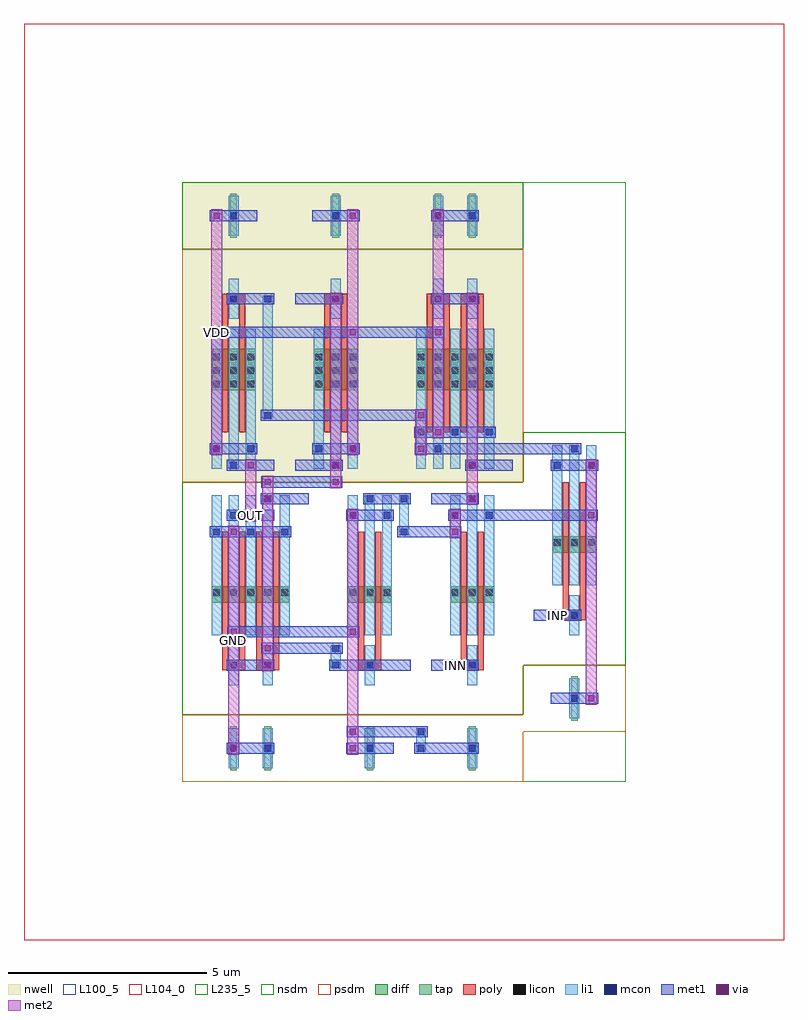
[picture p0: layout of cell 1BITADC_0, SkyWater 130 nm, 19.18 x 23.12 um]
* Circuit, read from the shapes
.subckt 1BITADC_0 GND INN INP OUT VDD
XM1 OUT n1 GND GND sky130_fd_pr__nfet_01v8 w=0.42 l=0.15 m=2
XM2 n1 n1 GND GND sky130_fd_pr__nfet_01v8 w=0.42 l=0.15 m=2
XM3 GND n1 GND GND sky130_fd_pr__nfet_01v8 w=0.42 l=0.15 m=2
XM4 n2 INN GND GND sky130_fd_pr__nfet_01v8 w=0.42 l=0.15 m=2
XM5 n3 INP GND GND sky130_fd_pr__nfet_01v8 w=0.42 l=0.15 m=2
XM6 OUT n3 VDD VDD sky130_fd_pr__pfet_01v8 w=1.05 l=0.15 m=2
XM7 n1 n1 VDD VDD sky130_fd_pr__pfet_01v8 w=1.05 l=0.15 m=2
XM8 n3 n2 VDD VDD sky130_fd_pr__pfet_01v8 w=1.05 l=0.15 m=2
XM9 n2 n2 VDD VDD sky130_fd_pr__pfet_01v8 w=1.05 l=0.15 m=2
.ends

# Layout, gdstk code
from math import pi, radians
import gdstk
lib = gdstk.Library(unit=1e-6, precision=1e-09)
def R(c, l, rs):  # rectangles x0, y0, x1, y1
    for r in rs: c.add(gdstk.rectangle(r[:2], r[2:], *l))
def A(c, l, x, y, w, h, nx, ny, dx, dy):  # array of equal rectangles
    R(c, l, [(x+i*dx, y+j*dy, x+i*dx+w, y+j*dy+h) for i in range(nx) for j in range(ny)])
def P(c, l, *ps):  # polygons
    for p in ps: c.add(gdstk.Polygon(p, *l))
nwell = (64, 20)
diff = (65, 20)
tap = (65, 44)
poly = (66, 20)
licon = (66, 44)
li1 = (67, 20)
mcon = (67, 44)
met1 = (68, 20)
via = (68, 44)
met2 = (69, 20)
nsdm = (93, 44)
psdm = (94, 20)
L100_5 = (100, 5)
L104_0 = (104, 0)
L235_5 = (235, 5)

scm_nmos_62702031_x1_y1_ = lib.new_cell('SCM_NMOS_62702031_X1_Y1_1678951898_1678951899')
R(scm_nmos_62702031_x1_y1_, diff, [(0.735,2.625,2.705,3.045)])
R(scm_nmos_62702031_x1_y1_, tap, [(1.205,6.16,1.375,7.28), (2.065,6.16,2.235,7.28)])
A(scm_nmos_62702031_x1_y1_, poly, 1, 1.26, 0.15, 3.36, 4, 1, 0.43, 0)
R(scm_nmos_62702031_x1_y1_, poly, [(1,4.485,1.58,4.755), (1.86,4.485,2.44,4.755)])
A(scm_nmos_62702031_x1_y1_, licon, 0.775, 2.705, 0.17, 0.17, 3, 1, 0.43, 0)
A(scm_nmos_62702031_x1_y1_, licon, 1.635, 2.705, 0.17, 0.17, 3, 1, 0.43, 0)
R(scm_nmos_62702031_x1_y1_, licon, [(1.205,4.535,1.375,4.705), (2.065,4.535,2.235,4.705), (1.205,6.635,1.375,6.805), (2.065,6.635,2.235,6.805)])
A(scm_nmos_62702031_x1_y1_, li1, 0.735, 0.335, 0.25, 3.53, 5, 1, 0.43, 0)
R(scm_nmos_62702031_x1_y1_, li1, [(1.165,4.115,1.415,5.125), (2.025,4.115,2.275,5.125), (1.165,6.215,1.415,7.225), (2.025,6.215,2.275,7.225)])
A(scm_nmos_62702031_x1_y1_, mcon, 0.775, 1.175, 0.17, 0.17, 3, 1, 0.86, 0)
R(scm_nmos_62702031_x1_y1_, mcon, [(1.205,0.335,1.375,0.505), (2.065,0.755,2.235,0.925), (1.205,4.535,1.375,4.705), (2.065,4.535,2.235,4.705), (1.205,6.635,1.375,6.805), (2.065,6.635,2.235,6.805)])
R(scm_nmos_62702031_x1_y1_, met1, [(0.26,0.28,1.46,0.56), (1.12,0.7,2.32,0.98), (0.69,1.12,2.75,1.4), (1.12,4.48,2.32,4.76), (1.12,6.58,2.32,6.86)])
R(scm_nmos_62702031_x1_y1_, via, [(1.215,0.345,1.365,0.495), (2.075,1.185,2.225,1.335), (1.215,4.545,1.365,4.695), (2.075,6.645,2.225,6.795)])
R(scm_nmos_62702031_x1_y1_, met2, [(1.15,0.26,1.43,4.78), (2.01,1.1,2.29,6.88)])
R(scm_nmos_62702031_x1_y1_, nsdm, [(0,0,3.44,5.88)])
R(scm_nmos_62702031_x1_y1_, psdm, [(0,5.88,3.44,7.56)])
R(scm_nmos_62702031_x1_y1_, L100_5, [(0,0,3.44,7.56)])

nmos_s_96839798_x1_y1_16 = lib.new_cell('NMOS_S_96839798_X1_Y1_1678951897_1678951899')
R(nmos_s_96839798_x1_y1_16, diff, [(0.735,2.625,1.845,3.045)])
R(nmos_s_96839798_x1_y1_16, tap, [(1.205,6.16,1.375,7.28)])
R(nmos_s_96839798_x1_y1_16, poly, [(1,1.26,1.15,4.62), (1.43,1.26,1.58,4.62), (1,4.485,1.58,4.755)])
A(nmos_s_96839798_x1_y1_16, licon, 0.775, 2.705, 0.17, 0.17, 3, 1, 0.43, 0)
R(nmos_s_96839798_x1_y1_16, licon, [(1.205,4.535,1.375,4.705), (1.205,6.635,1.375,6.805)])
A(nmos_s_96839798_x1_y1_16, li1, 0.735, 0.335, 0.25, 3.53, 3, 1, 0.43, 0)
R(nmos_s_96839798_x1_y1_16, li1, [(1.165,4.115,1.415,5.125), (1.165,6.215,1.415,7.225)])
R(nmos_s_96839798_x1_y1_16, mcon, [(1.205,0.335,1.375,0.505), (0.775,0.755,0.945,0.925), (1.635,0.755,1.805,0.925), (1.205,4.535,1.375,4.705), (1.205,6.635,1.375,6.805)])
R(nmos_s_96839798_x1_y1_16, met1, [(0.26,0.28,1.46,0.56), (0.69,0.7,1.89,0.98), (0.26,4.48,1.46,4.76), (0.69,6.58,1.89,6.86)])
R(nmos_s_96839798_x1_y1_16, via, [(1.645,0.765,1.795,0.915), (1.645,6.645,1.795,6.795)])
R(nmos_s_96839798_x1_y1_16, met2, [(1.58,0.68,1.86,6.88)])
R(nmos_s_96839798_x1_y1_16, nsdm, [(0,0,2.58,5.88)])
R(nmos_s_96839798_x1_y1_16, psdm, [(0,5.88,2.58,7.56)])
R(nmos_s_96839798_x1_y1_16, L100_5, [(0,0,2.58,7.56)])

cmb_nmos_2_97597727_0_0_ = lib.new_cell('CMB_NMOS_2_97597727_0_0_1678951899')
R(cmb_nmos_2_97597727_0_0_, li1, [(2.025,4.115,2.275,4.285), (2.025,4.115,2.275,4.285), (2.025,4.2,2.275,4.62), (2.025,4.535,2.275,4.705), (2.025,4.535,2.275,4.705)])
R(cmb_nmos_2_97597727_0_0_, mcon, [(2.065,4.115,2.235,4.285), (2.065,4.115,2.235,4.285), (2.065,4.535,2.235,4.705), (2.065,4.535,2.235,4.705)])
R(cmb_nmos_2_97597727_0_0_, met1, [(1.56,3.64,1.88,3.92), (1.56,3.64,1.88,3.92), (1.72,3.64,4.73,3.92), (4.57,3.64,4.89,3.92), (4.57,3.64,4.89,3.92), (1.98,4.06,2.32,4.34), (1.98,4.06,2.32,4.34), (2.15,4.06,3.87,4.34), (3.71,4.06,4.03,4.34), (3.71,4.06,4.03,4.34), (1.29,4.48,2.15,4.76), (1.98,4.48,2.32,4.76), (1.98,4.48,2.32,4.76)])
P(cmb_nmos_2_97597727_0_0_, met1, [(0,0),(0,0),(0,0),(0,0)],
  [(0,0),(0,0),(0,0),(0,0)],
  [(0,0),(0,0),(0,0),(0,0)])
R(cmb_nmos_2_97597727_0_0_, via, [(1.645,3.705,1.795,3.855), (1.645,3.705,1.795,3.855), (4.655,3.705,4.805,3.855), (4.655,3.705,4.805,3.855), (3.795,4.125,3.945,4.275), (3.795,4.125,3.945,4.275)])
R(cmb_nmos_2_97597727_0_0_, met2, [(1.58,3.62,1.86,3.94), (1.58,3.62,1.86,3.94), (4.59,3.62,4.87,3.94), (4.59,3.62,4.87,3.94), (3.73,4.04,4.01,4.36), (3.73,4.04,4.01,4.36)])
P(cmb_nmos_2_97597727_0_0_, met2, [(0,0),(0,0),(0,0),(0,0)],
  [(0,0),(0,0),(0,0),(0,0)],
  [(0,0),(0,0),(0,0),(0,0)])
R(cmb_nmos_2_97597727_0_0_, L235_5, [(0,0,6.02,7.56)])
cmb_nmos_2_97597727_0_0_.add(gdstk.Reference(scm_nmos_62702031_x1_y1_, (2.58,0)))
cmb_nmos_2_97597727_0_0_.add(gdstk.Reference(nmos_s_96839798_x1_y1_16, (0,0)))

scm_pmos_67707602_x1_y1_ = lib.new_cell('SCM_PMOS_67707602_X1_Y1_1678951904')
R(scm_pmos_67707602_x1_y1_, nwell, [(0,0,3.44,7.56)])
R(scm_pmos_67707602_x1_y1_, diff, [(0.735,2.31,2.705,3.36)])
R(scm_pmos_67707602_x1_y1_, tap, [(1.205,6.16,1.375,7.28), (2.065,6.16,2.235,7.28)])
A(scm_pmos_67707602_x1_y1_, poly, 1, 1.26, 0.15, 3.36, 4, 1, 0.43, 0)
R(scm_pmos_67707602_x1_y1_, poly, [(1,4.485,1.58,4.755), (1.86,4.485,2.44,4.755)])
A(scm_pmos_67707602_x1_y1_, licon, 0.775, 2.39, 0.17, 0.17, 3, 3, 0.43, 0.34)
A(scm_pmos_67707602_x1_y1_, licon, 1.635, 2.39, 0.17, 0.17, 3, 3, 0.43, 0.34)
R(scm_pmos_67707602_x1_y1_, licon, [(1.205,4.535,1.375,4.705), (2.065,4.535,2.235,4.705), (1.205,6.635,1.375,6.805), (2.065,6.635,2.235,6.805)])
A(scm_pmos_67707602_x1_y1_, li1, 0.735, 0.335, 0.25, 3.53, 5, 1, 0.43, 0)
R(scm_pmos_67707602_x1_y1_, li1, [(1.165,4.115,1.415,5.125), (2.025,4.115,2.275,5.125), (1.165,6.215,1.415,7.225), (2.025,6.215,2.275,7.225)])
A(scm_pmos_67707602_x1_y1_, mcon, 0.775, 1.175, 0.17, 0.17, 3, 1, 0.86, 0)
R(scm_pmos_67707602_x1_y1_, mcon, [(1.205,0.335,1.375,0.505), (2.065,0.755,2.235,0.925), (1.205,4.535,1.375,4.705), (2.065,4.535,2.235,4.705), (1.205,6.635,1.375,6.805), (2.065,6.635,2.235,6.805)])
R(scm_pmos_67707602_x1_y1_, met1, [(0.26,0.28,1.46,0.56), (1.12,0.7,2.32,0.98), (0.69,1.12,2.75,1.4), (1.12,4.48,2.32,4.76), (1.12,6.58,2.32,6.86)])
R(scm_pmos_67707602_x1_y1_, via, [(1.215,0.345,1.365,0.495), (2.075,1.185,2.225,1.335), (1.215,4.545,1.365,4.695), (2.075,6.645,2.225,6.795)])
R(scm_pmos_67707602_x1_y1_, met2, [(1.15,0.26,1.43,4.78), (2.01,1.1,2.29,6.88)])
R(scm_pmos_67707602_x1_y1_, nsdm, [(0,5.88,3.44,7.56)])
R(scm_pmos_67707602_x1_y1_, psdm, [(0,0,3.44,5.88)])
R(scm_pmos_67707602_x1_y1_, L100_5, [(0,0,3.44,7.56)])

dcl_pmos_s_45230142_x1_y = lib.new_cell('DCL_PMOS_S_45230142_X1_Y1_1678951900')
R(dcl_pmos_s_45230142_x1_y, nwell, [(0,0,2.58,7.56)])
R(dcl_pmos_s_45230142_x1_y, diff, [(0.735,2.31,1.845,3.36)])
R(dcl_pmos_s_45230142_x1_y, tap, [(1.205,6.16,1.375,7.28)])
R(dcl_pmos_s_45230142_x1_y, poly, [(1,1.26,1.15,4.62), (1.43,1.26,1.58,4.62), (1,4.485,1.58,4.755)])
A(dcl_pmos_s_45230142_x1_y, licon, 0.775, 2.39, 0.17, 0.17, 3, 3, 0.43, 0.34)
R(dcl_pmos_s_45230142_x1_y, licon, [(1.205,4.535,1.375,4.705), (1.205,6.635,1.375,6.805)])
A(dcl_pmos_s_45230142_x1_y, li1, 0.735, 0.335, 0.25, 3.53, 3, 1, 0.43, 0)
R(dcl_pmos_s_45230142_x1_y, li1, [(1.165,4.115,1.415,5.125), (1.165,6.215,1.415,7.225)])
R(dcl_pmos_s_45230142_x1_y, mcon, [(1.205,0.335,1.375,0.505), (0.775,0.755,0.945,0.925), (1.635,0.755,1.805,0.925), (1.205,4.535,1.375,4.705), (1.205,6.635,1.375,6.805)])
R(dcl_pmos_s_45230142_x1_y, met1, [(0.26,0.28,1.46,0.56), (0.69,0.7,1.89,0.98), (0.26,4.48,1.46,4.76), (0.69,6.58,1.89,6.86)])
R(dcl_pmos_s_45230142_x1_y, via, [(1.215,0.345,1.365,0.495), (1.645,0.765,1.795,0.915), (1.215,4.545,1.365,4.695), (1.645,6.645,1.795,6.795)])
R(dcl_pmos_s_45230142_x1_y, met2, [(1.15,0.26,1.43,4.78), (1.58,0.68,1.86,6.88)])
R(dcl_pmos_s_45230142_x1_y, nsdm, [(0,5.88,2.58,7.56)])
R(dcl_pmos_s_45230142_x1_y, psdm, [(0,0,2.58,5.88)])
R(dcl_pmos_s_45230142_x1_y, L100_5, [(0,0,2.58,7.56)])

c_nmos_s_96839798_x1_y1_16 = lib.new_cell('NMOS_S_96839798_X1_Y1_1678951902')
R(c_nmos_s_96839798_x1_y1_16, diff, [(0.735,2.625,1.845,3.045)])
R(c_nmos_s_96839798_x1_y1_16, tap, [(1.205,6.16,1.375,7.28)])
R(c_nmos_s_96839798_x1_y1_16, poly, [(1,1.26,1.15,4.62), (1.43,1.26,1.58,4.62), (1,4.485,1.58,4.755)])
A(c_nmos_s_96839798_x1_y1_16, licon, 0.775, 2.705, 0.17, 0.17, 3, 1, 0.43, 0)
R(c_nmos_s_96839798_x1_y1_16, licon, [(1.205,4.535,1.375,4.705), (1.205,6.635,1.375,6.805)])
A(c_nmos_s_96839798_x1_y1_16, li1, 0.735, 0.335, 0.25, 3.53, 3, 1, 0.43, 0)
R(c_nmos_s_96839798_x1_y1_16, li1, [(1.165,4.115,1.415,5.125), (1.165,6.215,1.415,7.225)])
R(c_nmos_s_96839798_x1_y1_16, mcon, [(1.205,0.335,1.375,0.505), (0.775,0.755,0.945,0.925), (1.635,0.755,1.805,0.925), (1.205,4.535,1.375,4.705), (1.205,6.635,1.375,6.805)])
R(c_nmos_s_96839798_x1_y1_16, met1, [(0.26,0.28,1.46,0.56), (0.69,0.7,1.89,0.98), (0.26,4.48,1.46,4.76), (0.69,6.58,1.89,6.86)])
R(c_nmos_s_96839798_x1_y1_16, via, [(1.645,0.765,1.795,0.915), (1.645,6.645,1.795,6.795)])
R(c_nmos_s_96839798_x1_y1_16, met2, [(1.58,0.68,1.86,6.88)])
R(c_nmos_s_96839798_x1_y1_16, nsdm, [(0,0,2.58,5.88)])
R(c_nmos_s_96839798_x1_y1_16, psdm, [(0,5.88,2.58,7.56)])
R(c_nmos_s_96839798_x1_y1_16, L100_5, [(0,0,2.58,7.56)])

pmos_s_3683112_x1_y1_167 = lib.new_cell('PMOS_S_3683112_X1_Y1_1678951903')
R(pmos_s_3683112_x1_y1_167, nwell, [(0,0,2.58,7.56)])
R(pmos_s_3683112_x1_y1_167, diff, [(0.735,2.31,1.845,3.36)])
R(pmos_s_3683112_x1_y1_167, tap, [(1.205,6.16,1.375,7.28)])
R(pmos_s_3683112_x1_y1_167, poly, [(1,1.26,1.15,4.62), (1.43,1.26,1.58,4.62), (1,4.485,1.58,4.755)])
A(pmos_s_3683112_x1_y1_167, licon, 0.775, 2.39, 0.17, 0.17, 3, 3, 0.43, 0.34)
R(pmos_s_3683112_x1_y1_167, licon, [(1.205,4.535,1.375,4.705), (1.205,6.635,1.375,6.805)])
A(pmos_s_3683112_x1_y1_167, li1, 0.735, 0.335, 0.25, 3.53, 3, 1, 0.43, 0)
R(pmos_s_3683112_x1_y1_167, li1, [(1.165,4.115,1.415,5.125), (1.165,6.215,1.415,7.225)])
R(pmos_s_3683112_x1_y1_167, mcon, [(1.205,0.335,1.375,0.505), (0.775,0.755,0.945,0.925), (1.635,0.755,1.805,0.925), (1.205,4.535,1.375,4.705), (1.205,6.635,1.375,6.805)])
R(pmos_s_3683112_x1_y1_167, met1, [(0.26,0.28,1.46,0.56), (0.69,0.7,1.89,0.98), (0.26,4.48,1.46,4.76), (0.69,6.58,1.89,6.86)])
R(pmos_s_3683112_x1_y1_167, via, [(1.645,0.765,1.795,0.915), (1.645,6.645,1.795,6.795)])
R(pmos_s_3683112_x1_y1_167, met2, [(1.58,0.68,1.86,6.88)])
R(pmos_s_3683112_x1_y1_167, nsdm, [(0,5.88,2.58,7.56)])
R(pmos_s_3683112_x1_y1_167, psdm, [(0,0,2.58,5.88)])
R(pmos_s_3683112_x1_y1_167, L100_5, [(0,0,2.58,7.56)])

nmos_4t_65417822_x1_y1_1 = lib.new_cell('NMOS_4T_65417822_X1_Y1_1678951901')
R(nmos_4t_65417822_x1_y1_1, diff, [(0.735,2.625,1.845,3.045)])
R(nmos_4t_65417822_x1_y1_1, tap, [(1.205,6.16,1.375,7.28)])
R(nmos_4t_65417822_x1_y1_1, poly, [(1,1.26,1.15,4.62), (1.43,1.26,1.58,4.62), (1,4.485,1.58,4.755)])
A(nmos_4t_65417822_x1_y1_1, licon, 0.775, 2.705, 0.17, 0.17, 3, 1, 0.43, 0)
R(nmos_4t_65417822_x1_y1_1, licon, [(1.205,4.535,1.375,4.705), (1.205,6.635,1.375,6.805)])
A(nmos_4t_65417822_x1_y1_1, li1, 0.735, 0.335, 0.25, 3.53, 3, 1, 0.43, 0)
R(nmos_4t_65417822_x1_y1_1, li1, [(1.165,4.115,1.415,5.125), (1.165,6.215,1.415,7.225)])
R(nmos_4t_65417822_x1_y1_1, mcon, [(1.205,0.335,1.375,0.505), (0.775,0.755,0.945,0.925), (1.635,0.755,1.805,0.925), (1.205,4.535,1.375,4.705), (1.205,6.635,1.375,6.805)])
R(nmos_4t_65417822_x1_y1_1, met1, [(0.26,0.28,1.46,0.56), (0.69,0.7,1.89,0.98), (0.26,4.48,1.46,4.76), (0.26,6.58,1.46,6.86)])
R(nmos_4t_65417822_x1_y1_1, nsdm, [(0,0,2.58,5.88)])
R(nmos_4t_65417822_x1_y1_1, psdm, [(0,5.88,2.58,7.56)])
R(nmos_4t_65417822_x1_y1_1, L100_5, [(0,0,2.58,7.56)])

c_1bitadc_0 = lib.new_cell('1BITADC_0')
R(c_1bitadc_0, li1, [(5.895,0.755,6.145,0.925), (5.895,0.755,6.145,0.925), (5.895,0.84,6.145,1.26), (5.895,1.175,6.145,1.345), (5.895,1.175,6.145,1.345), (5.465,6.215,5.715,6.385), (5.465,6.215,5.715,6.385), (5.465,6.215,5.715,6.385), (5.465,6.215,5.715,6.385), (5.465,6.3,5.715,7.14), (5.465,7.055,5.715,7.225), (5.465,7.055,5.715,7.225), (5.465,7.055,5.715,7.225), (5.465,7.055,5.715,7.225), (2.025,9.155,2.275,9.325), (2.025,9.155,2.275,9.325), (2.025,9.155,2.275,9.325), (2.025,9.155,2.275,9.325), (2.025,9.24,2.275,12.18), (2.025,12.095,2.275,12.265), (2.025,12.095,2.275,12.265), (2.025,12.095,2.275,12.265), (2.025,12.095,2.275,12.265)])
P(c_1bitadc_0, li1, [(0,0),(0,0),(0,0),(0,0)])
R(c_1bitadc_0, mcon, [(5.935,0.755,6.105,0.925), (5.935,0.755,6.105,0.925), (5.935,1.175,6.105,1.345), (5.935,1.175,6.105,1.345), (5.505,6.215,5.675,6.385), (5.505,6.215,5.675,6.385), (5.505,6.215,5.675,6.385), (5.505,6.215,5.675,6.385), (5.505,7.055,5.675,7.225), (5.505,7.055,5.675,7.225), (5.505,7.055,5.675,7.225), (5.505,7.055,5.675,7.225), (2.065,9.155,2.235,9.325), (2.065,9.155,2.235,9.325), (2.065,9.155,2.235,9.325), (2.065,9.155,2.235,9.325), (2.065,12.095,2.235,12.265), (2.065,12.095,2.235,12.265), (2.065,12.095,2.235,12.265), (2.065,12.095,2.235,12.265)])
R(c_1bitadc_0, met1, [(5.85,0.7,6.19,0.98), (5.85,0.7,6.19,0.98), (6.02,0.7,6.45,0.98), (4.14,1.12,4.46,1.4), (4.14,1.12,4.46,1.4), (4.3,1.12,6.02,1.4), (5.85,1.12,6.19,1.4), (5.85,1.12,6.19,1.4), (5.42,6.16,5.76,6.44), (5.42,6.16,5.76,6.44), (5.42,6.16,5.76,6.44), (5.42,6.16,5.76,6.44), (5.59,6.16,6.88,6.44), (6.72,6.16,7.04,6.44), (6.72,6.16,7.04,6.44), (6.72,6.16,7.04,6.44), (6.72,6.16,7.04,6.44), (1.56,6.58,1.88,6.86), (1.56,6.58,1.88,6.86), (6.72,6.58,7.04,6.86), (6.72,6.58,7.04,6.86), (6.72,6.58,7.04,6.86), (6.72,6.58,7.04,6.86), (7.74,6.58,10.32,6.86), (10.16,6.58,10.48,6.86), (10.16,6.58,10.48,6.86), (5.42,7,5.76,7.28), (5.42,7,5.76,7.28), (5.42,7,5.76,7.28), (5.42,7,5.76,7.28), (7.15,7,7.47,7.28), (7.15,7,7.47,7.28), (1.99,7.42,2.31,7.7), (1.99,7.42,2.31,7.7), (2.15,7.42,3.87,7.7), (3.71,7.42,4.03,7.7), (3.71,7.42,4.03,7.7), (1.56,7.84,1.88,8.12), (1.56,7.84,1.88,8.12), (5.86,8.26,6.18,8.54), (5.86,8.26,6.18,8.54), (5.86,8.26,6.18,8.54), (5.86,8.26,6.18,8.54), (6.02,8.26,6.45,8.54), (7.31,8.26,9.03,8.54), (1.98,9.1,2.32,9.38), (1.98,9.1,2.32,9.38), (1.98,9.1,2.32,9.38), (1.98,9.1,2.32,9.38), (2.15,9.1,6.02,9.38), (5.86,9.1,6.18,9.38), (5.86,9.1,6.18,9.38), (5.86,9.1,6.18,9.38), (5.86,9.1,6.18,9.38), (0.7,11.2,1.02,11.48), (0.7,11.2,1.02,11.48), (0.7,11.2,1.02,11.48), (0.7,11.2,1.02,11.48), (0.86,11.2,4.3,11.48), (4.14,11.2,4.46,11.48), (4.14,11.2,4.46,11.48), (4.14,11.2,4.46,11.48), (4.14,11.2,4.46,11.48), (4.3,11.2,6.45,11.48), (6.29,11.2,6.61,11.48), (6.29,11.2,6.61,11.48), (1.98,12.04,2.32,12.32), (1.98,12.04,2.32,12.32), (1.98,12.04,2.32,12.32), (1.98,12.04,2.32,12.32)])
P(c_1bitadc_0, met1, [(0,0),(0,0),(0,0),(0,0)],
  [(0,0),(0,0),(0,0),(0,0)],
  [(0,0),(0,0),(0,0),(0,0)],
  [(0,0),(0,0),(0,0),(0,0)],
  [(0,0),(0,0),(0,0),(0,0)],
  [(0,0),(0,0),(0,0),(0,0)],
  [(0,0),(0,0),(0,0),(0,0)],
  [(0,0),(0,0),(0,0),(0,0)],
  [(0,0),(0,0),(0,0),(0,0)],
  [(0,0),(0,0),(0,0),(0,0)],
  [(0,0),(0,0),(0,0),(0,0)],
  [(0,0),(0,0),(0,0),(0,0)],
  [(0,0),(0,0),(0,0),(0,0)],
  [(0,0),(0,0),(0,0),(0,0)],
  [(0,0),(0,0),(0,0),(0,0)],
  [(0,0),(0,0),(0,0),(0,0)],
  [(0,0),(0,0),(0,0),(0,0)],
  [(0,0),(0,0),(0,0),(0,0)])
R(c_1bitadc_0, via, [(4.225,1.185,4.375,1.335), (4.225,1.185,4.375,1.335), (6.805,6.225,6.955,6.375), (6.805,6.225,6.955,6.375), (6.805,6.225,6.955,6.375), (6.805,6.225,6.955,6.375), (1.645,6.645,1.795,6.795), (1.645,6.645,1.795,6.795), (6.805,6.645,6.955,6.795), (6.805,6.645,6.955,6.795), (6.805,6.645,6.955,6.795), (6.805,6.645,6.955,6.795), (10.245,6.645,10.395,6.795), (10.245,6.645,10.395,6.795), (7.235,7.065,7.385,7.215), (7.235,7.065,7.385,7.215), (2.075,7.485,2.225,7.635), (2.075,7.485,2.225,7.635), (3.795,7.485,3.945,7.635), (3.795,7.485,3.945,7.635), (1.645,7.905,1.795,8.055), (1.645,7.905,1.795,8.055), (5.945,8.325,6.095,8.475), (5.945,8.325,6.095,8.475), (5.945,8.325,6.095,8.475), (5.945,8.325,6.095,8.475), (5.945,9.165,6.095,9.315), (5.945,9.165,6.095,9.315), (5.945,9.165,6.095,9.315), (5.945,9.165,6.095,9.315), (0.785,11.265,0.935,11.415), (0.785,11.265,0.935,11.415), (0.785,11.265,0.935,11.415), (0.785,11.265,0.935,11.415), (4.225,11.265,4.375,11.415), (4.225,11.265,4.375,11.415), (4.225,11.265,4.375,11.415), (4.225,11.265,4.375,11.415), (6.375,11.265,6.525,11.415), (6.375,11.265,6.525,11.415)])
R(c_1bitadc_0, met2, [(4.16,1.1,4.44,1.42), (4.16,1.1,4.44,1.42), (6.74,6.14,7.02,6.46), (6.74,6.14,7.02,6.46), (6.74,6.14,7.02,6.46), (6.74,6.14,7.02,6.46), (6.74,6.3,7.02,6.72), (1.58,6.56,1.86,6.88), (1.58,6.56,1.86,6.88), (6.74,6.56,7.02,6.88), (6.74,6.56,7.02,6.88), (6.74,6.56,7.02,6.88), (6.74,6.56,7.02,6.88), (10.18,6.56,10.46,6.88), (10.18,6.56,10.46,6.88), (1.58,6.72,1.86,7.98), (7.17,6.98,7.45,7.3), (7.17,6.98,7.45,7.3), (2.01,7.14,2.29,7.56), (7.17,7.14,7.45,7.98), (2.01,7.4,2.29,7.72), (2.01,7.4,2.29,7.72), (3.73,7.4,4.01,7.72), (3.73,7.4,4.01,7.72), (3.73,7.56,4.01,7.98), (1.58,7.82,1.86,8.14), (1.58,7.82,1.86,8.14), (5.88,8.24,6.16,8.56), (5.88,8.24,6.16,8.56), (5.88,8.24,6.16,8.56), (5.88,8.24,6.16,8.56), (5.88,8.4,6.16,9.24), (5.88,9.08,6.16,9.4), (5.88,9.08,6.16,9.4), (5.88,9.08,6.16,9.4), (5.88,9.08,6.16,9.4), (0.72,11.18,1,11.5), (0.72,11.18,1,11.5), (0.72,11.18,1,11.5), (0.72,11.18,1,11.5), (4.16,11.18,4.44,11.5), (4.16,11.18,4.44,11.5), (4.16,11.18,4.44,11.5), (4.16,11.18,4.44,11.5), (6.31,11.18,6.59,11.5), (6.31,11.18,6.59,11.5)])
P(c_1bitadc_0, met2, [(0,0),(0,0),(0,0),(0,0)],
  [(0,0),(0,0),(0,0),(0,0)],
  [(0,0),(0,0),(0,0),(0,0)],
  [(0,0),(0,0),(0,0),(0,0)],
  [(0,0),(0,0),(0,0),(0,0)],
  [(0,0),(0,0),(0,0),(0,0)],
  [(0,0),(0,0),(0,0),(0,0)],
  [(0,0),(0,0),(0,0),(0,0)],
  [(0,0),(0,0),(0,0),(0,0)],
  [(0,0),(0,0),(0,0),(0,0)],
  [(0,0),(0,0),(0,0),(0,0)],
  [(0,0),(0,0),(0,0),(0,0)],
  [(0,0),(0,0),(0,0),(0,0)],
  [(0,0),(0,0),(0,0),(0,0)])
R(c_1bitadc_0, L104_0, [(-4,-4,15.18,19.12)])
R(c_1bitadc_0, L235_5, [(0,0,11.18,15.12)])
c_1bitadc_0.add(gdstk.Reference(cmb_nmos_2_97597727_0_0_, (6.02,7.56), rotation=pi))
c_1bitadc_0.add(gdstk.Reference(scm_pmos_67707602_x1_y1_, (8.6,7.56), rotation=pi, x_reflection=True))
c_1bitadc_0.add(gdstk.Reference(dcl_pmos_s_45230142_x1_y, (2.58,7.56)))
c_1bitadc_0.add(gdstk.Reference(c_nmos_s_96839798_x1_y1_16, (8.6,8.82), x_reflection=True))
c_1bitadc_0.add(gdstk.Reference(pmos_s_3683112_x1_y1_167, (2.58,7.56), rotation=pi, x_reflection=True))
c_1bitadc_0.add(gdstk.Reference(nmos_4t_65417822_x1_y1_1, (6.02,7.56), x_reflection=True))
c_1bitadc_0.add(gdstk.Label('OUT', (1.72,6.72), layer=68, texttype=5))
c_1bitadc_0.add(gdstk.Label('GND', (1.29,3.57), layer=69, texttype=5))
c_1bitadc_0.add(gdstk.Label('VDD', (0.86,11.34), layer=69, texttype=5))
c_1bitadc_0.add(gdstk.Label('INP', (9.46,4.2), layer=68, texttype=5))
c_1bitadc_0.add(gdstk.Label('INN', (6.88,2.94), layer=68, texttype=5))

lib.write_gds('1BITADC_0.gds')
